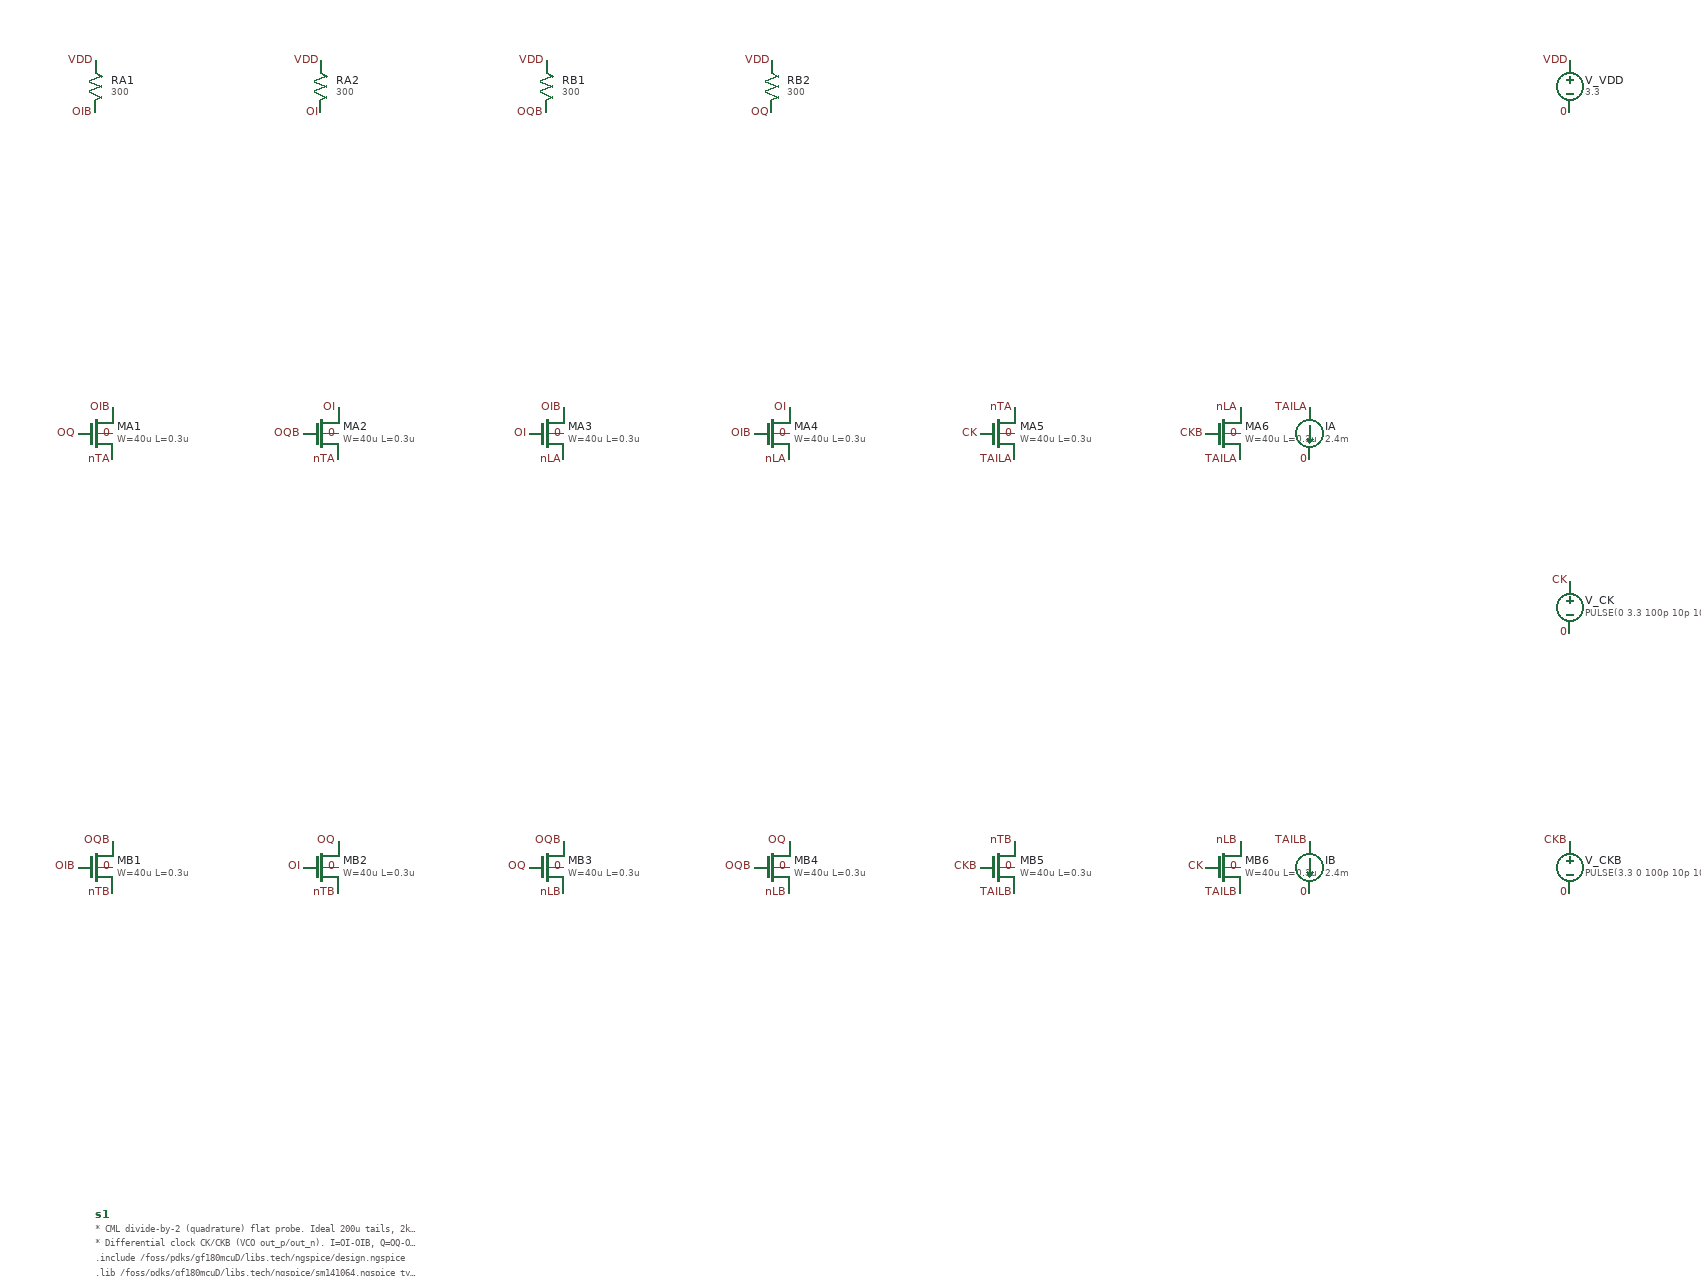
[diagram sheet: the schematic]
v {xschem version=3.4.8RC file_version=1.3}
G {}
K {}
V {}
S {}
F {}
E {}
C {symbols/nfet_03v3.sym} 0 0 0 0 {name=MA1 L=0.3u W=40u nf=1 model=nfet_03v3 spiceprefix=X}
C {lab_pin.sym} -20 0 0 0 {name=lp1 lab=OQ}
C {lab_pin.sym} 20 -30 0 0 {name=lp2 lab=OIB}
C {lab_pin.sym} 20 30 0 0 {name=lp3 lab=nTA}
C {lab_pin.sym} 20 0 0 0 {name=lp4 lab=0}
C {symbols/nfet_03v3.sym} 260 0 0 0 {name=MA2 L=0.3u W=40u nf=1 model=nfet_03v3 spiceprefix=X}
C {lab_pin.sym} 240 0 0 0 {name=lp5 lab=OQB}
C {lab_pin.sym} 280 -30 0 0 {name=lp6 lab=OI}
C {lab_pin.sym} 280 30 0 0 {name=lp7 lab=nTA}
C {lab_pin.sym} 280 0 0 0 {name=lp8 lab=0}
C {symbols/nfet_03v3.sym} 520 0 0 0 {name=MA3 L=0.3u W=40u nf=1 model=nfet_03v3 spiceprefix=X}
C {lab_pin.sym} 500 0 0 0 {name=lp9 lab=OI}
C {lab_pin.sym} 540 -30 0 0 {name=lp10 lab=OIB}
C {lab_pin.sym} 540 30 0 0 {name=lp11 lab=nLA}
C {lab_pin.sym} 540 0 0 0 {name=lp12 lab=0}
C {symbols/nfet_03v3.sym} 780 0 0 0 {name=MA4 L=0.3u W=40u nf=1 model=nfet_03v3 spiceprefix=X}
C {lab_pin.sym} 760 0 0 0 {name=lp13 lab=OIB}
C {lab_pin.sym} 800 -30 0 0 {name=lp14 lab=OI}
C {lab_pin.sym} 800 30 0 0 {name=lp15 lab=nLA}
C {lab_pin.sym} 800 0 0 0 {name=lp16 lab=0}
C {symbols/nfet_03v3.sym} 1040 0 0 0 {name=MA5 L=0.3u W=40u nf=1 model=nfet_03v3 spiceprefix=X}
C {lab_pin.sym} 1020 0 0 0 {name=lp17 lab=CK}
C {lab_pin.sym} 1060 -30 0 0 {name=lp18 lab=nTA}
C {lab_pin.sym} 1060 30 0 0 {name=lp19 lab=TAILA}
C {lab_pin.sym} 1060 0 0 0 {name=lp20 lab=0}
C {symbols/nfet_03v3.sym} 1300 0 0 0 {name=MA6 L=0.3u W=40u nf=1 model=nfet_03v3 spiceprefix=X}
C {lab_pin.sym} 1280 0 0 0 {name=lp21 lab=CKB}
C {lab_pin.sym} 1320 -30 0 0 {name=lp22 lab=nLA}
C {lab_pin.sym} 1320 30 0 0 {name=lp23 lab=TAILA}
C {lab_pin.sym} 1320 0 0 0 {name=lp24 lab=0}
C {symbols/nfet_03v3.sym} 0 500 0 0 {name=MB1 L=0.3u W=40u nf=1 model=nfet_03v3 spiceprefix=X}
C {lab_pin.sym} -20 500 0 0 {name=lp25 lab=OIB}
C {lab_pin.sym} 20 470 0 0 {name=lp26 lab=OQB}
C {lab_pin.sym} 20 530 0 0 {name=lp27 lab=nTB}
C {lab_pin.sym} 20 500 0 0 {name=lp28 lab=0}
C {symbols/nfet_03v3.sym} 260 500 0 0 {name=MB2 L=0.3u W=40u nf=1 model=nfet_03v3 spiceprefix=X}
C {lab_pin.sym} 240 500 0 0 {name=lp29 lab=OI}
C {lab_pin.sym} 280 470 0 0 {name=lp30 lab=OQ}
C {lab_pin.sym} 280 530 0 0 {name=lp31 lab=nTB}
C {lab_pin.sym} 280 500 0 0 {name=lp32 lab=0}
C {symbols/nfet_03v3.sym} 520 500 0 0 {name=MB3 L=0.3u W=40u nf=1 model=nfet_03v3 spiceprefix=X}
C {lab_pin.sym} 500 500 0 0 {name=lp33 lab=OQ}
C {lab_pin.sym} 540 470 0 0 {name=lp34 lab=OQB}
C {lab_pin.sym} 540 530 0 0 {name=lp35 lab=nLB}
C {lab_pin.sym} 540 500 0 0 {name=lp36 lab=0}
C {symbols/nfet_03v3.sym} 780 500 0 0 {name=MB4 L=0.3u W=40u nf=1 model=nfet_03v3 spiceprefix=X}
C {lab_pin.sym} 760 500 0 0 {name=lp37 lab=OQB}
C {lab_pin.sym} 800 470 0 0 {name=lp38 lab=OQ}
C {lab_pin.sym} 800 530 0 0 {name=lp39 lab=nLB}
C {lab_pin.sym} 800 500 0 0 {name=lp40 lab=0}
C {symbols/nfet_03v3.sym} 1040 500 0 0 {name=MB5 L=0.3u W=40u nf=1 model=nfet_03v3 spiceprefix=X}
C {lab_pin.sym} 1020 500 0 0 {name=lp41 lab=CKB}
C {lab_pin.sym} 1060 470 0 0 {name=lp42 lab=nTB}
C {lab_pin.sym} 1060 530 0 0 {name=lp43 lab=TAILB}
C {lab_pin.sym} 1060 500 0 0 {name=lp44 lab=0}
C {symbols/nfet_03v3.sym} 1300 500 0 0 {name=MB6 L=0.3u W=40u nf=1 model=nfet_03v3 spiceprefix=X}
C {lab_pin.sym} 1280 500 0 0 {name=lp45 lab=CK}
C {lab_pin.sym} 1320 470 0 0 {name=lp46 lab=nLB}
C {lab_pin.sym} 1320 530 0 0 {name=lp47 lab=TAILB}
C {lab_pin.sym} 1320 500 0 0 {name=lp48 lab=0}
C {res.sym} 0 -400 0 0 {name=RA1 value=300 footprint=1206 device=resistor m=1}
C {lab_pin.sym} 0 -430 0 0 {name=lp49 lab=VDD}
C {lab_pin.sym} 0 -370 0 0 {name=lp50 lab=OIB}
C {res.sym} 260 -400 0 0 {name=RA2 value=300 footprint=1206 device=resistor m=1}
C {lab_pin.sym} 260 -430 0 0 {name=lp51 lab=VDD}
C {lab_pin.sym} 260 -370 0 0 {name=lp52 lab=OI}
C {res.sym} 520 -400 0 0 {name=RB1 value=300 footprint=1206 device=resistor m=1}
C {lab_pin.sym} 520 -430 0 0 {name=lp53 lab=VDD}
C {lab_pin.sym} 520 -370 0 0 {name=lp54 lab=OQB}
C {res.sym} 780 -400 0 0 {name=RB2 value=300 footprint=1206 device=resistor m=1}
C {lab_pin.sym} 780 -430 0 0 {name=lp55 lab=VDD}
C {lab_pin.sym} 780 -370 0 0 {name=lp56 lab=OQ}
C {isource.sym} 1400 0 0 0 {name=IA value=2.4m}
C {lab_pin.sym} 1400 -30 0 0 {name=lp57 lab=TAILA}
C {lab_pin.sym} 1400 30 0 0 {name=lp58 lab=0}
C {isource.sym} 1400 500 0 0 {name=IB value=2.4m}
C {lab_pin.sym} 1400 470 0 0 {name=lp59 lab=TAILB}
C {lab_pin.sym} 1400 530 0 0 {name=lp60 lab=0}
C {vsource.sym} 1700 -400 0 0 {name=V_VDD value="3.3" savecurrent=false}
C {lab_pin.sym} 1700 -430 0 0 {name=lp61 lab=VDD}
C {lab_pin.sym} 1700 -370 0 0 {name=lp62 lab=0}
C {vsource.sym} 1700 200 0 0 {name=V_CK value="PULSE(0 3.3 100p 10p 10p 90p 200p)" savecurrent=false}
C {lab_pin.sym} 1700 170 0 0 {name=lp63 lab=CK}
C {lab_pin.sym} 1700 230 0 0 {name=lp64 lab=0}
C {vsource.sym} 1700 500 0 0 {name=V_CKB value="PULSE(3.3 0 100p 10p 10p 90p 200p)" savecurrent=false}
C {lab_pin.sym} 1700 470 0 0 {name=lp65 lab=CKB}
C {lab_pin.sym} 1700 530 0 0 {name=lp66 lab=0}
C {code_shown.sym} 0 900 0 0 {name=s1 only_toplevel=false value="
* CML divide-by-2 (quadrature) flat probe. Ideal 200u tails, 2k loads.
* Differential clock CK/CKB (VCO out_p/out_n). I=OI-OIB, Q=OQ-OQB @ CK/2.
.include /foss/pdks/gf180mcuD/libs.tech/ngspice/design.ngspice
.lib /foss/pdks/gf180mcuD/libs.tech/ngspice/sm141064.ngspice typical
"}
